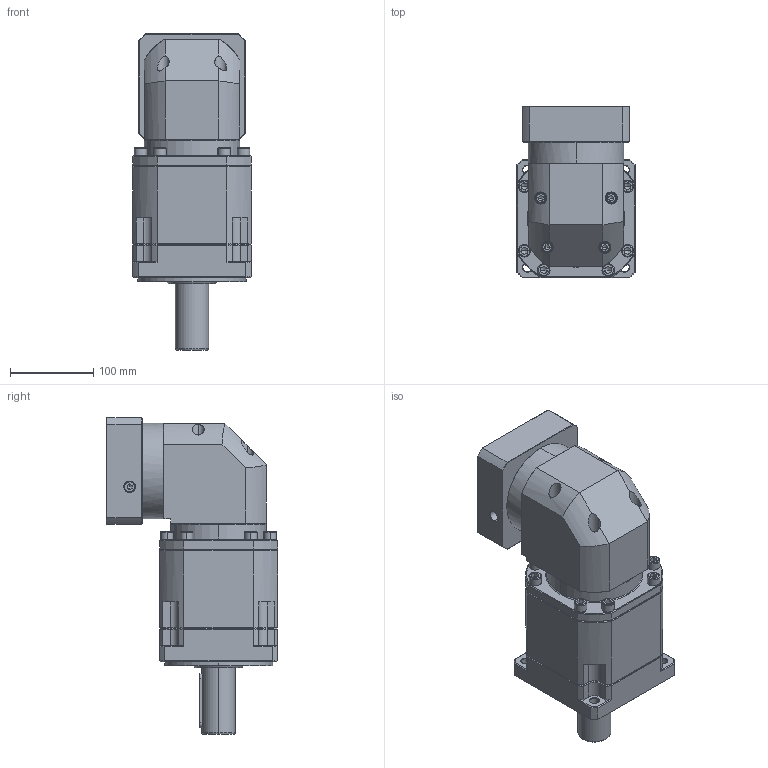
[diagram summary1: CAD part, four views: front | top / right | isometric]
STEP (ISO 10303-21) file: header records copied from the file, then geometry measured from it (millimetres).
FILE_DESCRIPTION (( 'STEP AP214' ), '1' );
FILE_NAME ('ZBR142A-D40-L3-P2-24-110-145-M8.step', '2023-09-02T08:11:30', ( '' ), ( '' ), 'SwSTEP 2.0', 'SolidWorks 2016', '' );
FILE_SCHEMA (( 'AUTOMOTIVE_DESIGN' ));
Length unit declared in the file: millimetre
Products named in the file (1): ZBR142A-D40-L3-P2-24-110-145-M8
Bounding box: 142 x 205.9 x 380.2 mm (x, y, z)
Volume: 5224173.4 mm3; surface area: 344408 mm2
Topology: 6 solids, 6 shells, 2589 faces, 6737 edges, 4274 vertices
Faces by surface type: plane 1232, cylinder 502, bspline 410, cone 399, torus 46
Entity records: 137003 total; most frequent: CARTESIAN_POINT 48518, ORIENTED_EDGE 13366, DIRECTION 10937, EDGE_CURVE 6683, VECTOR 4275, LINE 4275, VERTEX_POINT 4274, AXIS2_PLACEMENT_3D 3331
One B-rep face of a CAD part: STEP entity #64995.
In plain terms, the planar face has unit normal (0, 0, 1).
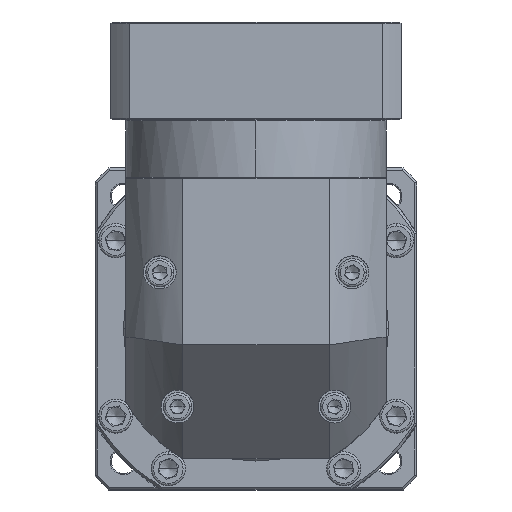
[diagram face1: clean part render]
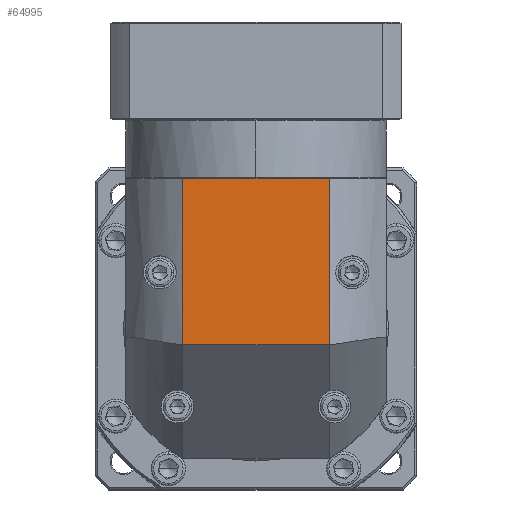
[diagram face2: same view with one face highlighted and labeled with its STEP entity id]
Its self-contained STEP definition (entity closure, numbers rounded to 3 decimals):
#10611 = ORIENTED_EDGE ( 'NONE', *, *, #85972, .F. ) ;
#11205 = VECTOR ( 'NONE', #118231, 1000. ) ;
#25529 = LINE ( 'NONE', #117235, #11205 ) ;
#25797 = AXIS2_PLACEMENT_3D ( 'NONE', #35631, #114786, #67520 ) ;
#28303 = CARTESIAN_POINT ( 'NONE',  ( -114.922, 31.856, 109.27 ) ) ;
#32403 = LINE ( 'NONE', #28303, #51920 ) ;
#35631 = CARTESIAN_POINT ( 'NONE',  ( -147.322, 89.356, 109.27 ) ) ;
#36406 = CARTESIAN_POINT ( 'NONE',  ( -179.722, 81.856, 109.27 ) ) ;
#36953 = ORIENTED_EDGE ( 'NONE', *, *, #84469, .F. ) ;
#38801 = ORIENTED_EDGE ( 'NONE', *, *, #134981, .F. ) ;
#40176 = DIRECTION ( 'NONE',  ( 0., -1., 0. ) ) ;
#41776 = VERTEX_POINT ( 'NONE', #36406 ) ;
#51920 = VECTOR ( 'NONE', #40176, 1000. ) ;
#52006 = VERTEX_POINT ( 'NONE', #79171 ) ;
#54183 = EDGE_CURVE ( 'NONE', #41776, #91103, #112530, .T. ) ;
#55542 = CARTESIAN_POINT ( 'NONE',  ( -204.822, 81.856, 109.27 ) ) ;
#57036 = PLANE ( 'NONE',  #25797 ) ;
#57987 = VERTEX_POINT ( 'NONE', #124821 ) ;
#64995 = ADVANCED_FACE ( 'NONE', ( #135911 ), #57036, .F. ) ;
#67520 = DIRECTION ( 'NONE',  ( 1., 0., 0. ) ) ;
#69795 = ORIENTED_EDGE ( 'NONE', *, *, #54183, .F. ) ;
#79171 = CARTESIAN_POINT ( 'NONE',  ( -114.922, 155.256, 109.27 ) ) ;
#84469 = EDGE_CURVE ( 'NONE', #57987, #41776, #87851, .T. ) ;
#85972 = EDGE_CURVE ( 'NONE', #52006, #57987, #32403, .T. ) ;
#87851 = LINE ( 'NONE', #55542, #91424 ) ;
#91103 = VERTEX_POINT ( 'NONE', #94456 ) ;
#91424 = VECTOR ( 'NONE', #112283, 1000. ) ;
#94456 = CARTESIAN_POINT ( 'NONE',  ( -179.722, 155.256, 109.27 ) ) ;
#101857 = CARTESIAN_POINT ( 'NONE',  ( -179.722, 31.856, 109.27 ) ) ;
#107213 = VECTOR ( 'NONE', #147606, 1000. ) ;
#110434 = EDGE_LOOP ( 'NONE', ( #69795, #36953, #10611, #38801 ) ) ;
#112283 = DIRECTION ( 'NONE',  ( -1., 0., 0. ) ) ;
#112530 = LINE ( 'NONE', #101857, #107213 ) ;
#114786 = DIRECTION ( 'NONE',  ( 0., 0., -1. ) ) ;
#117235 = CARTESIAN_POINT ( 'NONE',  ( -204.822, 155.256, 109.27 ) ) ;
#118231 = DIRECTION ( 'NONE',  ( 1., 0., 0. ) ) ;
#124821 = CARTESIAN_POINT ( 'NONE',  ( -114.922, 81.856, 109.27 ) ) ;
#134981 = EDGE_CURVE ( 'NONE', #91103, #52006, #25529, .T. ) ;
#135911 = FACE_OUTER_BOUND ( 'NONE', #110434, .T. ) ;
#147606 = DIRECTION ( 'NONE',  ( 0., 1., 0. ) ) ;
